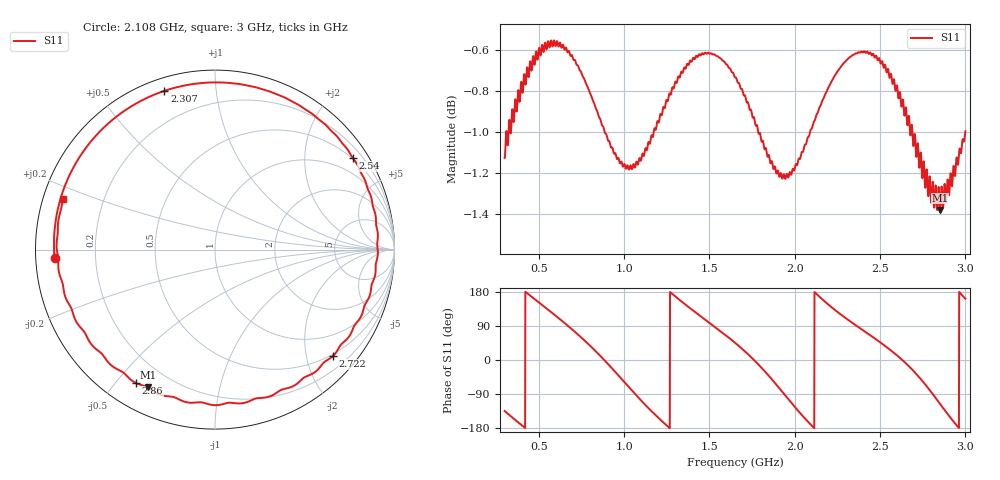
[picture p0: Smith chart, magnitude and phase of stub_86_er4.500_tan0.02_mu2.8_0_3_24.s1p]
! Chirptenna · simulación 3D de un stub abierto
# HZ S RI R 50
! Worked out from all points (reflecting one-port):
!   2001 points, 300 MHz to 3 GHz, reference 50 ohm
!   lowest |S11| = -1.4 dB at 2.852 GHz (marker M1), VSWR 12.63, Z = 5.49 - j31 ohm
!   phase of S11 starts at -135 deg and turns -1144 deg over the sweep
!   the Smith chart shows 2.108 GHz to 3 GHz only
!   S11 on the Smith chart (normalised r, x): 2.108 GHz: 0.06, -0.03; 2.307 GHz: 0.06, +0.73; 2.54 GHz: 0.48, +3.24; 2.722 GHz: 0.46, -2.54; 2.86 GHz: 0.10, -0.57; 3 GHz: 0.06, +0.16
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3e8  -0.6159 -0.6265
4.593e8  -0.898 0.2131
6.375e8  -0.2076 0.9118
7.3605e8  0.3931 0.8357
8.3595e8  0.8358 0.3415
9.75e8  0.6219 -0.6168
1.0452e9  0.1507 -0.8599
1.1127e9  -0.3435 -0.81
1.2126e9  -0.8319 -0.3444
1.3125e9  -0.8786 0.2648
1.488e9  -0.198 0.9103
1.65e9  0.6418 0.6578
1.73505e9  0.8841 0.1826
1.80795e9  0.8248 -0.325
1.90515e9  0.2686 -0.8286
1.9875e9  -0.3958 -0.7781
2.10765e9  -0.8941 -0.0489
2.30745e9  -0.2816 0.8845
2.325e9  -0.1932 0.9093
2.43165e9  0.3399 0.8672
2.53965e9  0.7667 0.5114
2.6625e9  0.8705 -0.2094
2.7219e9  0.6587 -0.5914
2.7867e9  0.1976 -0.8421
2.8515e9  -0.374 -0.7669
2.8596e9  -0.441 -0.743
2.92575e9  -0.8141 -0.3032
3e9  -0.8465 0.2804
